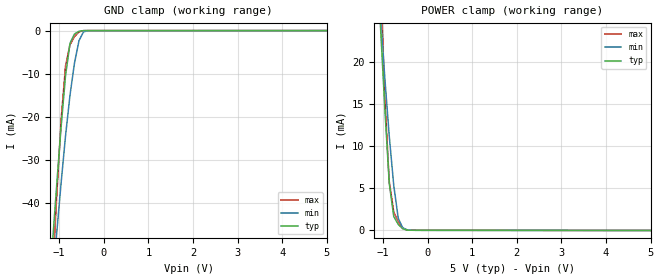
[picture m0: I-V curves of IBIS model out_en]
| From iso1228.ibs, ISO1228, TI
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|   Model out_en
[Model] out_en
Model_type Input
Vinl =  1.500V
Vinh =  3.500V
C_comp   0.993pF   1.060pF   0.895pF
[Model Spec]
Vinh   3.500V   3.150V   3.850V
Vinl   1.500V   1.350V   1.650V
[Temperature Range]   27.000   0.150k   -40.000
[Voltage Range]   5.000V   4.500V   5.500V
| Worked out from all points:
|   GND clamp passes 1 mA (typ) near -0.67 V on its own axis
|   POWER clamp passes 1 mA (typ) near -0.69 V on its own axis
[GND_clamp]
|Voltage   I(typ)   I(min)   I(max)
-5V       -818.7mA   -676.3mA   -1.205A
-1.162V   -51.06mA   -60.02mA   -59.3mA
-1.061V   -36.53mA   -47.61mA   -39.37mA
-960mV    -22.69mA   -35.66mA   -21.17mA
-859mV    -10.57mA   -24.51mA   -8.289mA
-758mV    -2.933mA   -14.98mA   -3.269mA
-657mV    -791.5uA   -7.512mA   -1.385mA
-556mV    -157.5uA   -2.326mA   -289.5uA
-455mV    -12.34uA   -296.6uA   -14.34uA
-354mV    -1.829uA   -25.8uA    -1.977uA
5V        0A         0A         0A
[POWER_clamp]
|Voltage   I(typ)   I(min)   I(max)
-5V       612mA      452.6mA    1.004A
-1.061V   24.82mA    26.01mA    31.1mA
-960mV    14.7mA     18.27mA    15.98mA
-859mV    5.624mA    11.22mA    5.819mA
-758mV    1.661mA    5.362mA    2.204mA
-657mV    720.8uA    1.451mA    1.049mA
-556mV    202.9uA    318.4uA    253.6uA
-455mV    36.45uA    70.18uA    40.07uA
-253mV    21.02uA    17.25uA    29.76uA
5V        0A         0A         2.586uA
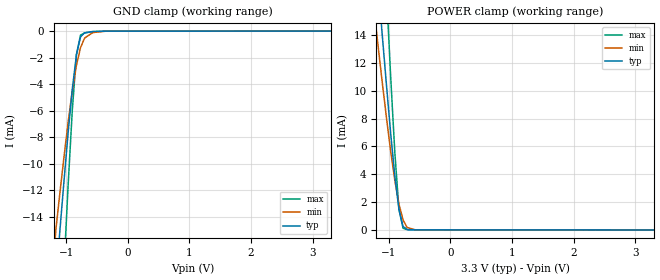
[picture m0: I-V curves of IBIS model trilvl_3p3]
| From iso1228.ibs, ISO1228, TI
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|   Model trilvl_3p3
[Model] trilvl_3p3
Model_type Input
Vinl =  0.000V
Vinh =  3.300V
C_comp   0.541pF   0.630pF   0.4235pF
[Model Spec]
Vinh   3.3V   3.00V   3.60V
Vinl   0.0V   0.0V   0.0V
[Temperature Range]   27.000   0.150k   -40.000
[Voltage Range]   3.300V   3.000V   3.600V
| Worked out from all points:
|   GND clamp passes 1 mA (typ) near -0.79 V on its own axis
|   POWER clamp passes 1 mA (typ) near -0.81 V on its own axis
[GND_clamp]
|Voltage   I(typ)   I(min)   I(max)
-3.3V     -218.7mA   -148.2mA   -389.8mA
-1.167V   -18.85mA   -15mA      -30.75mA
-1.1V     -14.97mA   -12.16mA   -24.15mA
-1.033V   -11.21mA   -9.418mA   -17.71mA
-967mV    -7.622mA   -6.84mA    -11.55mA
-900mV    -4.371mA   -4.512mA   -5.957mA
-833mV    -1.795mA   -2.584mA   -1.765mA
-767mV    -442.9uA   -1.248mA   -305.4uA
-700mV    -127.6uA   -523.3uA   -137.3uA
-567mV    -29.95uA   -111.7uA   -44.09uA
-367mV    -8.141uA   -11.8uA    -11.24uA
3.3V      0A         0A         0A
[POWER_clamp]
|Voltage   I(typ)   I(min)   I(max)
-3.3V     208mA      137.3mA    378.9mA
-1.233V   21.08mA    15.67mA    35.85mA
-1.167V   17.4mA     13.03mA    29.42mA
-1.1V     13.79mA    10.45mA    23.1mA
-1.033V   10.27mA    7.97mA     16.91mA
-967mV    6.924mA    5.637mA    10.98mA
-900mV    3.878mA    3.55mA     5.565mA
-833mV    1.472mA    1.863mA    1.486mA
-767mV    259uA      725.5uA    127.4uA
-700mV    30.73uA    177.8uA    19.36uA
-567mV    9.093uA    11.33uA    12.26uA
3.3V      0A         0A         0A
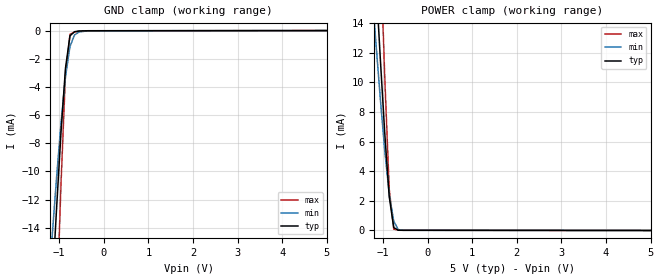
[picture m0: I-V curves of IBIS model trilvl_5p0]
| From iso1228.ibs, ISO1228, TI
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|   Model trilvl_5p0
[Model] trilvl_5p0
Model_type Input
Vinl =  0.000V
Vinh =  5.000V
C_comp   0.541pF   0.630pF   0.4235pF
[Model Spec]
Vinh   5.0V   4.5V   5.5V
Vinl   0.0V   0.0V   0.0V
[Temperature Range]   27.000   0.150k   -40.000
[Voltage Range]   5.000V   4.500V   5.500V
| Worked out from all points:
|   GND clamp passes 1 mA (typ) near -0.79 V on its own axis
|   POWER clamp passes 1 mA (typ) near -0.80 V on its own axis
[GND_clamp]
|Voltage   I(typ)   I(min)   I(max)
-5V       -427.2mA   -303.5mA   -743.4mA
-1.162V   -18.57mA   -14.79mA   -30.26mA
-1.061V   -12.75mA   -10.53mA   -20.34mA
-960mV    -7.245mA   -6.602mA   -10.92mA
-859mV    -2.674mA   -3.274mA   -3.061mA
-758mV    -369.2uA   -1.128mA   -265.7uA
-657mV    -81.82uA   -313.2uA   -104.9uA
-556mV    -29.88uA   -102.3uA   -43.38uA
-354mV    -11.46uA   -13.34uA   -16.05uA
5V        0A         0A         0A
[POWER_clamp]
|Voltage   I(typ)   I(min)   I(max)
-5V       408.8mA    285.2mA    753.9mA
-1.263V   22.72mA    16.85mA    38.69mA
-1.162V   17.13mA    12.83mA    28.95mA
-1.061V   11.7mA     8.974mA    19.43mA
-960mV    6.586mA    5.404mA    10.38mA
-859mV    2.278mA    2.446mA    2.776mA
-758mV    194.8uA    619.2uA    94.54uA
-657mV    16.65uA    62.67uA    18.77uA
-556mV    12.33uA    12.87uA    17.11uA
5V        0A         0A         0A
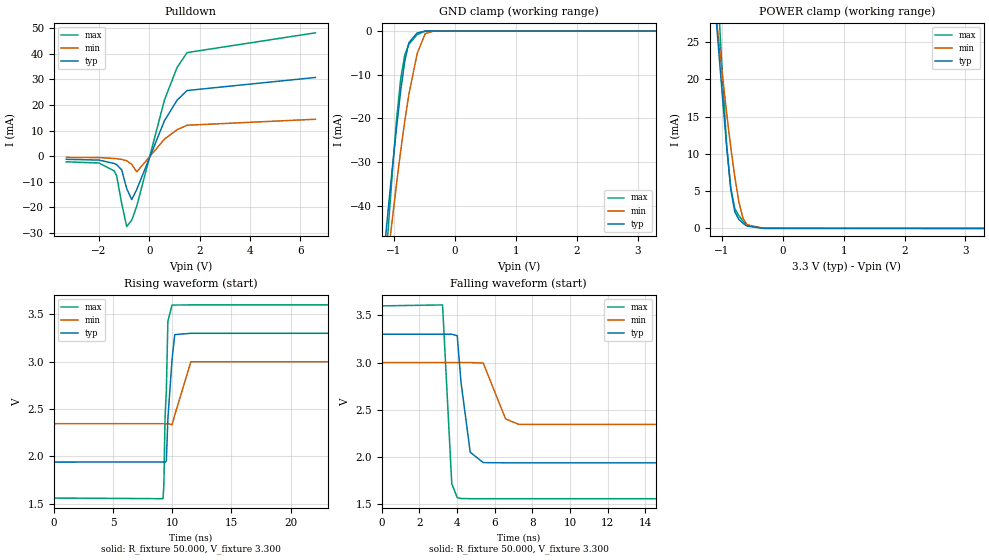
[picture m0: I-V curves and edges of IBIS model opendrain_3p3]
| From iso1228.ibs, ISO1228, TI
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|   Model opendrain_3p3
[Model] opendrain_3p3
Model_type Open_drain
Polarity   Inverting
Enable   Active-High
Vmeas = 1.65
Vref = 0
Cref = 15pF
Rref = 1000
C_comp   0.978pF   1.050pF   0.889pF
[Temperature Range]   27.000   0.150k   -40.000
[Voltage Range]   3.300V   3.000V   3.600V
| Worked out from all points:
|   slope of the pulldown table from 0 to 0.495 V, typ, clamps not added: 42.1 ohm
|   GND clamp passes 1 mA (typ) near -0.68 V on its own axis
|   POWER clamp passes 1 mA (typ) near -0.69 V on its own axis
|   rising waveform, R_fixture 50.000, V_fixture 3.300: 20-80 % time 392ps typ, 740ps min, 248ps max; typ from 1.94 V to 3.3 V
|   falling waveform, R_fixture 50.000, V_fixture 3.300: 20-80 % time 463ps typ, 870ps min, 299ps max; typ from 3.3 V to 1.94 V
[Pulldown]
|Voltage   I(typ)   I(min)   I(max)
-3.3V     -1.27mA    -512.7uA   -2.251mA
-2V       -1.57mA    -587.2uA   -2.712mA
-1.4V     -2.883mA   -944.2uA   -5.78mA
-1.3V     -3.347mA   -1.041mA   -7.661mA
-1.1V     -5.362mA   -1.308mA   -18.45mA
-900mV    -12.72mA   -1.811mA   -27.59mA
-700mV    -17.04mA   -3.28mA    -25.07mA
-500mV    -13.06mA   -6.173mA   -19.62mA
600mV     13.83mA    6.607mA    21.92mA
1.1V      21.83mA    10.3mA     34.62mA
1.5V      25.65mA    12.06mA    40.48mA
6.6V      30.76mA    14.41mA    48.22mA
[GND_clamp]
|Voltage   I(typ)   I(min)   I(max)
-3.3V     -446.5mA   -372.3mA   -652.2mA
-1.156V   -49.8mA    -58.79mA   -57.62mA
-1.089V   -40.16mA   -50.57mA   -44.34mA
-1.022V   -30.78mA   -42.53mA   -31.63mA
-955mV    -21.82mA   -34.73mA   -20.01mA
-888mV    -13.57mA   -27.32mA   -10.88mA
-821mV    -6.782mA   -20.5mA    -5.378mA
-754mV    -2.661mA   -14.48mA   -3.017mA
-620mV    -440.3uA   -5.22mA    -824.4uA
-486mV    -24.32uA   -589.1uA   -33.38uA
-352mV    -955.4nA   -22.22uA   -1.004uA
3.3V      0A         0A         0A
[POWER_clamp]
|Voltage   I(typ)   I(min)   I(max)
-3.3V     327.5mA    237.7mA    524.4mA
-1.122V   31.16mA    30.74mA    40.6mA
-1.055V   24.23mA    25.55mA    30.21mA
-988mV    17.47mA    20.39mA    20.09mA
-921mV    11mA       15.46mA    11.22mA
-854mV    5.281mA    10.91mA    5.481mA
-787mV    2.222mA    6.909mA    2.665mA
-720mV    1.205mA    3.542mA    1.718mA
-653mV    681.8uA    1.361mA    991.8uA
-586mV    305.3uA    487.1uA    416.2uA
-318mV    7.36uA     8.209uA    10.15uA
3.3V      0A         0A         775.8nA
[Ramp]
| variable   typ   min   max
dV/dt_r   0.817/0.392n   0.393/0.741n   1.225/0.249n
dV/dt_f   0.817/0.463n   0.393/0.874n   1.225/0.298n
R_load = 50.000
[Rising Waveform]
R_fixture= 50.000
V_fixture= 3.300
V_fixture_min= 3.000
V_fixture_max= 3.600
|time   V(typ)   V(min)   V(max)
0s        1.938V     2.344V     1.558V
9.22ns    1.939V     2.344V     1.551V
9.29ns    1.939V     2.344V     1.697V
9.39ns    1.933V     2.344V     2.407V
9.5ns     1.951V     2.344V     2.691V
9.63ns    2.398V     2.345V     3.429V
9.98ns    3.022V     2.333V     3.598V
10.21ns   3.286V     2.436V     3.599V
11.57ns   3.3V       2.999V     3.6V
100ns     3.3V       3V         3.6V
[Falling Waveform]
R_fixture= 50.000
V_fixture= 3.300
V_fixture_min= 3.000
V_fixture_max= 3.600
|time   V(typ)   V(min)   V(max)
0s        3.3V       3V         3.6V
3.23ns    3.3V       3V         3.61V
3.72ns    3.3V       3V         1.715V
4.01ns    3.285V     3V         1.57V
4.21ns    2.792V     3V         1.56V
4.7ns     2.05V      3V         1.558V
5.39ns    1.94V      2.994V     1.558V
6.58ns    1.938V     2.403V     1.558V
7.28ns    1.938V     2.345V     1.558V
100ns     1.938V     2.344V     1.558V
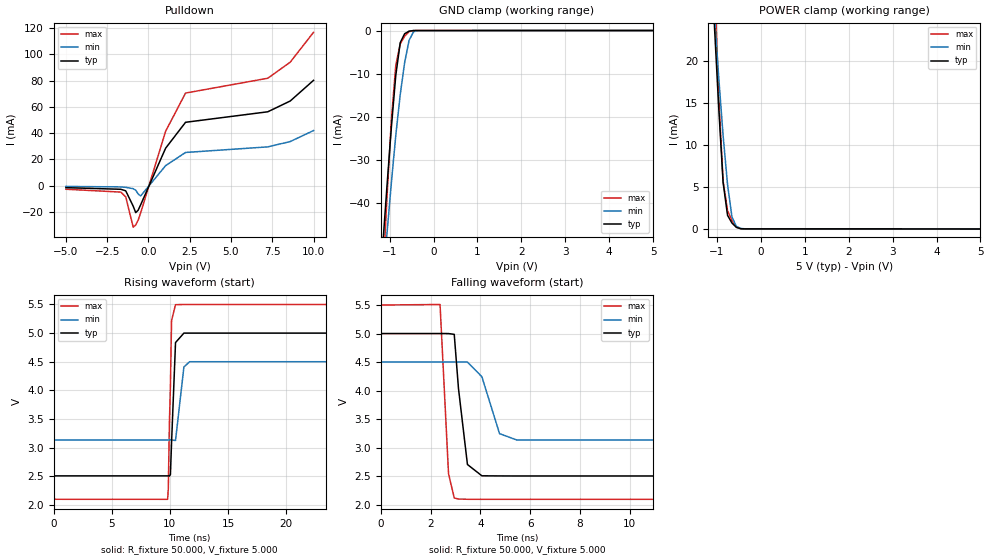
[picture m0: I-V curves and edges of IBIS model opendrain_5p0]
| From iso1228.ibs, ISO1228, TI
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|   Model opendrain_5p0
[Model] opendrain_5p0
Model_type Open_drain
Polarity   Inverting
Enable   Active-High
Vmeas = 2.5
Vref = 0
Cref = 15pF
Rref = 1000
C_comp   0.978pF   1.050pF   0.889pF
[Temperature Range]   27.000   0.150k   -40.000
[Voltage Range]   5.000V   4.500V   5.500V
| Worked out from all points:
|   slope of the pulldown table from 0 to 0.75 V, typ, clamps not added: 34.8 ohm
|   GND clamp passes 1 mA (typ) near -0.67 V on its own axis
|   POWER clamp passes 1 mA (typ) near -0.69 V on its own axis
|   rising waveform, R_fixture 50.000, V_fixture 5.000: 20-80 % time 273ps typ, 477ps min, 189ps max; typ from 2.5 V to 5 V
|   falling waveform, R_fixture 50.000, V_fixture 5.000: 20-80 % time 335ps typ, 576ps min, 230ps max; typ from 5 V to 2.5 V
[Pulldown]
|Voltage   I(typ)   I(min)   I(max)
-5V       -1.61mA    -692.2uA   -2.808mA
-1.678V   -2.831mA   -1.036mA   -4.975mA
-1.376V   -4.021mA   -1.338mA   -8.6mA
-923mV    -15.73mA   -2.397mA   -31.71mA
-772mV    -20.64mA   -3.559mA   -30.03mA
-621mV    -18.76mA   -6.434mA   -26.27mA
-470mV    -14.62mA   -7.875mA   -20.73mA
1.04V     28.46mA    15.18mA    41.37mA
2.248V    48.23mA    25.22mA    70.5mA
7.231V    56.23mA    29.49mA    81.81mA
8.59V     64.46mA    33.54mA    94.07mA
10V       80.2mA     41.93mA    116.8mA
[GND_clamp]
|Voltage   I(typ)   I(min)   I(max)
-5V       -814.6mA   -672.4mA   -1.2A
-1.162V   -50.67mA   -59.53mA   -58.82mA
-1.061V   -36.2mA    -47.19mA   -38.95mA
-960mV    -22.47mA   -35.3mA    -20.81mA
-859mV    -10.39mA   -24.29mA   -8.062mA
-758mV    -2.822mA   -14.82mA   -3.109mA
-657mV    -734.2uA   -7.408mA   -1.298mA
-556mV    -141uA     -2.276mA   -261.8uA
-455mV    -9.935uA   -286.2uA   -10.9uA
-354mV    -979nA     -23.38uA   -1.02uA
5V        0A         0A         0A
[POWER_clamp]
|Voltage   I(typ)   I(min)   I(max)
-5V       612mA      452.6mA    1.004A
-1.06V    24.74mA    25.95mA    30.99mA
-959mV    14.63mA    18.22mA    15.88mA
-858mV    5.569mA    11.17mA    5.743mA
-757mV    1.636mA    5.322mA    2.179mA
-656mV    705.3uA    1.427mA    1.027mA
-555mV    187.6uA    306.8uA    234.2uA
-454mV    24.09uA    60.92uA    22.38uA
-353mV    11.15uA    14.09uA    15.21uA
5V        0A         0A         1.293uA
[Ramp]
| variable   typ   min   max
dV/dt_r   1.497/0.272n   0.820/0.477n   2.042/0.188n
dV/dt_f   1.497/0.336n   0.820/0.574n   2.042/0.232n
R_load = 50.000
[Rising Waveform]
R_fixture= 50.000
V_fixture= 5.000
V_fixture_min= 4.500
V_fixture_max= 5.500
|time   V(typ)   V(min)   V(max)
0s        2.505V     3.133V     2.096V
9.81ns    2.505V     3.133V     2.095V
9.87ns    2.506V     3.132V     2.281V
9.96ns    2.502V     3.132V     3.402V
10.05ns   2.526V     3.133V     4.067V
10.15ns   3.09V      3.133V     5.216V
10.49ns   4.834V     3.123V     5.496V
11.21ns   4.999V     4.408V     5.499V
11.71ns   4.999V     4.499V     5.499V
100ns     5V         4.5V       5.499V
[Falling Waveform]
R_fixture= 50.000
V_fixture= 5.000
V_fixture_min= 4.500
V_fixture_max= 5.500
|time   V(typ)   V(min)   V(max)
0s        5V         4.5V       5.499V
2.38ns    5V         4.5V       5.508V
2.72ns    4.999V     4.5V       2.546V
2.95ns    4.985V     4.5V       2.12V
3.12ns    4.038V     4.5V       2.101V
3.48ns    2.706V     4.5V       2.097V
4.06ns    2.508V     4.243V     2.096V
4.77ns    2.506V     3.246V     2.096V
5.47ns    2.505V     3.134V     2.096V
100ns     2.505V     3.133V     2.096V
